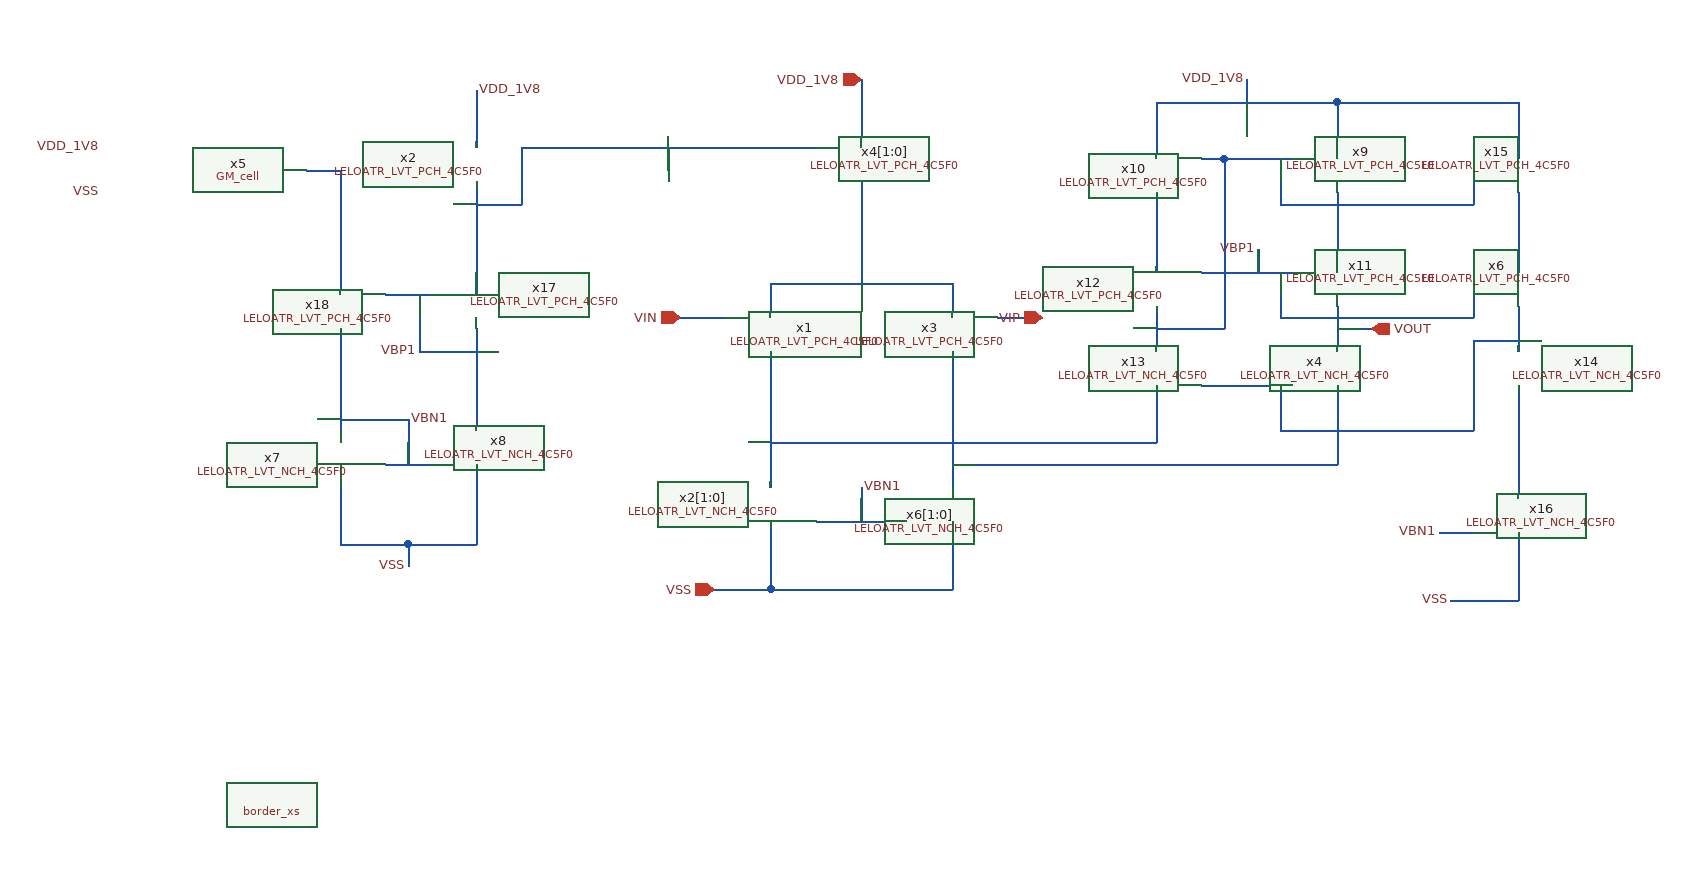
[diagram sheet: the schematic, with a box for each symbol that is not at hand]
v {xschem version=3.4.7 file_version=1.2}
G {}
K {}
V {}
S {}
E {}
P 4 1 20 30 {}
P 4 1 -120 -290 {}
N 440 -400 440 -380 {lab=#net1}
N 360 -430 400 -430 {lab=VIN}
N 640 -430 680 -430 {lab=VIP}
N 600 -400 600 -380 {lab=#net2}
N 440 -460 510 -460 {lab=#net3}
N 510 -460 600 -460 {lab=#net3}
N 520 -550 520 -460 {lab=#net3}
N 520 -640 520 -610 {lab=VDD_1V8}
N 100 -300 140 -300 {lab=VBN1}
N 120 -340 120 -300 {lab=VBN1}
N 60 -340 120 -340 {lab=VBN1}
N 120 -230 120 -210 {lab=VSS}
N 180 -340 180 -330 {lab=VBP1}
N 220 -580 220 -530 {lab=#net4}
N 180 -630 180 -610 {lab=VDD_1V8}
N 520 -610 520 -580 {lab=VDD_1V8}
N 180 -610 180 -580 {lab=VDD_1V8}
N 180 -300 180 -270 {lab=VSS}
N 60 -300 60 -270 {lab=VSS}
N 440 -250 440 -220 {lab=VSS}
N 600 -250 600 -220 {lab=VSS}
N 440 -380 440 -280 {lab=#net1}
N 600 -380 600 -280 {lab=#net2}
N 480 -250 560 -250 {lab=VBN1}
N 520 -280 520 -250 {lab=VBN1}
N 180 -530 220 -530 {lab=#net4}
N 220 -580 480 -580 {lab=#net4}
N 350 -580 350 -560 {lab=#net4}
N 780 -600 780 -570 {lab=VDD_1V8}
N 940 -600 940 -570 {lab=VDD_1V8}
N 780 -620 780 -600 {lab=VDD_1V8}
N 940 -620 940 -600 {lab=VDD_1V8}
N 780 -620 940 -620 {lab=VDD_1V8}
N 860 -640 860 -620 {lab=VDD_1V8}
N 820 -470 900 -470 {lab=VBP1}
N 780 -500 780 -470 {lab=#net5}
N 940 -500 940 -470 {lab=#net6}
N 780 -440 780 -400 {lab=#net7}
N 940 -440 940 -400 {lab=VOUT}
N 780 -540 780 -500 {lab=#net5}
N 940 -540 940 -500 {lab=#net6}
N 840 -570 840 -420 {lab=#net7}
N 780 -420 840 -420 {lab=#net7}
N 820 -370 900 -370 {lab=#net8}
N 940 -340 940 -300 {lab=#net2}
N 600 -300 940 -300 {lab=#net2}
N 780 -340 780 -320 {lab=#net1}
N 440 -320 780 -320 {lab=#net1}
N 440 -220 440 -190 {lab=VSS}
N 390 -190 440 -190 {lab=VSS}
N 600 -220 600 -190 {lab=VSS}
N 440 -190 600 -190 {lab=VSS}
N 780 -370 780 -340 {lab=#net1}
N 940 -370 940 -340 {lab=#net2}
N 940 -420 970 -420 {lab=VOUT}
N 870 -490 870 -470 {lab=VBP1}
N 60 -350 60 -330 {lab=VBN1}
N 60 -500 60 -490 {lab=#net9}
N 180 -360 180 -340 {lab=VBP1}
N 180 -270 180 -230 {lab=VSS}
N 120 -230 180 -230 {lab=VSS}
N 60 -230 120 -230 {lab=VSS}
N 60 -270 60 -230 {lab=VSS}
N 30 -560 60 -560 {lab=#net9}
N 440 -460 440 -430 {lab=#net3}
N 600 -460 600 -430 {lab=#net3}
N 180 -550 180 -500 {lab=#net4}
N 60 -560 60 -500 {lab=#net9}
N 1100 -210 1100 -180 {lab=VSS}
N 1040 -180 1100 -180 {lab=VSS}
N 1100 -240 1100 -210 {lab=VSS}
N 1100 -370 1100 -340 {lab=#net10}
N 1100 -340 1100 -270 {lab=#net10}
N 1030 -240 1060 -240 {lab=VBN1}
N 1100 -440 1100 -400 {lab=#net8}
N 1100 -540 1100 -500 {lab=#net11}
N 1100 -620 1100 -600 {lab=VDD_1V8}
N 940 -620 1100 -620 {lab=VDD_1V8}
N 1100 -600 1100 -570 {lab=VDD_1V8}
N 1100 -500 1100 -470 {lab=#net11}
N 820 -570 840 -570 {lab=#net7}
N 840 -570 900 -570 {lab=#net7}
N 890 -570 890 -530 {lab=#net7}
N 890 -530 1060 -530 {lab=#net7}
N 1060 -570 1060 -530 {lab=#net7}
N 890 -470 890 -430 {lab=VBP1}
N 890 -430 1060 -430 {lab=VBP1}
N 1060 -470 1060 -430 {lab=VBP1}
N 890 -370 890 -330 {lab=#net8}
N 890 -330 1060 -330 {lab=#net8}
N 1060 -370 1060 -330 {lab=#net8}
N 1060 -410 1060 -370 {lab=#net8}
N 1060 -410 1100 -410 {lab=#net8}
N 180 -500 180 -480 {lab=#net4}
N 100 -450 140 -450 {lab=VBP1}
N 60 -420 60 -350 {lab=VBN1}
N 180 -420 180 -360 {lab=VBP1}
N 60 -480 60 -450 {lab=#net9}
N 60 -490 60 -480 {lab=#net9}
N 180 -480 180 -450 {lab=#net4}
N 130 -450 130 -400 {lab=VBP1}
N 130 -400 180 -400 {lab=VBP1}
C {cborder/border_xs.sym} 0 0 0 0 {
user="nikolai"
company="wulff"}
C {devices/ipin.sym} 520 -640 0 0 {name=p1 lab=VDD_1V8}
C {devices/ipin.sym} 360 -430 0 0 {name=p4 lab=VIN}
C {devices/ipin.sym} 680 -430 2 0 {name=p5 lab=VIP}
C {devices/opin.sym} 970 -420 0 0 {name=p6 lab=VOUT}
C {LELO_ATR_SKY130A/LELOATR_LVT_PCH_4C5F0.sym} 400 -430 0 0 {name=x1 }
C {LELO_ATR_SKY130A/LELOATR_LVT_PCH_4C5F0.sym} 480 -580 0 0 {name=x4[1:0]}
C {LELO_ATR_SKY130A/LELOATR_LVT_PCH_4C5F0.sym} 640 -430 0 1 {name=x3 }
C {devices/ipin.sym} 390 -190 0 0 {name=p2 lab=VSS}
C {LELO_ATR_SKY130A/LELOATR_LVT_NCH_4C5F0.sym} 560 -250 0 0 {name=x6[1:0]}
C {LELO_ATR_SKY130A/LELOATR_LVT_NCH_4C5F0.sym} 480 -250 0 1 {name=x2[1:0]}
C {LELO_ATR_SKY130A/LELOATR_LVT_NCH_4C5F0.sym} 100 -300 0 1 {name=x7}
C {LELO_ATR_SKY130A/LELOATR_LVT_NCH_4C5F0.sym} 140 -300 0 0 {name=x8}
C {devices/lab_pin.sym} 120 -210 0 0 {name=p8 sig_type=std_logic lab=VSS}
C {LELO_ATR_SKY130A/LELOATR_LVT_PCH_4C5F0.sym} 220 -580 0 1 {name=x2}
C {devices/lab_pin.sym} 180 -630 0 1 {name=p9 sig_type=std_logic lab=VDD_1V8}
C {devices/lab_pin.sym} 120 -340 0 1 {name=p10 sig_type=std_logic lab=VBN1}
C {devices/lab_pin.sym} 520 -280 0 1 {name=p11 sig_type=std_logic lab=VBN1}
C {LELO_ATR_SKY130A/LELOATR_LVT_NCH_4C5F0.sym} 900 -370 0 0 {name=x4 }
C {LELO_ATR_SKY130A/LELOATR_LVT_PCH_4C5F0.sym} 900 -570 0 0 {name=x9}
C {LELO_ATR_SKY130A/LELOATR_LVT_PCH_4C5F0.sym} 820 -570 0 1 {name=x10}
C {devices/lab_pin.sym} 130 -400 0 0 {name=p12 sig_type=std_logic lab=VBP1}
C {devices/lab_pin.sym} 860 -640 0 0 {name=p13 sig_type=std_logic lab=VDD_1V8}
C {LELO_ATR_SKY130A/LELOATR_LVT_PCH_4C5F0.sym} 900 -470 0 0 {name=x11}
C {LELO_ATR_SKY130A/LELOATR_LVT_PCH_4C5F0.sym} 820 -470 0 1 {name=x12}
C {LELO_ATR_SKY130A/LELOATR_LVT_NCH_4C5F0.sym} 820 -370 0 1 {name=x13 }
C {devices/lab_pin.sym} 870 -490 0 0 {name=p14 sig_type=std_logic lab=VBP1}
C {LELO_ATR_SKY130A/LELOATR_LVT_PCH_4C5F0.sym} 1060 -570 0 0 {name=x15}
C {LELO_ATR_SKY130A/LELOATR_LVT_PCH_4C5F0.sym} 1060 -470 0 0 {name=x6}
C {LELO_ATR_SKY130A/LELOATR_LVT_NCH_4C5F0.sym} 1060 -370 0 0 {name=x14 }
C {LELO_ATR_SKY130A/LELOATR_LVT_NCH_4C5F0.sym} 1060 -240 0 0 {name=x16}
C {devices/lab_pin.sym} 1040 -180 0 0 {name=p16 sig_type=std_logic lab=VSS}
C {devices/lab_pin.sym} 1030 -240 0 0 {name=p17 sig_type=std_logic lab=VBN1}
C {LELO_GR01_SKY130A/GM_cell.sym} 0 -570 0 0 {name=x5}
C {devices/lab_pin.sym} -150 -580 0 0 {name=p3 sig_type=std_logic lab=VDD_1V8}
C {devices/lab_pin.sym} -150 -540 0 0 {name=p7 sig_type=std_logic lab=VSS}
C {LELO_ATR_SKY130A/LELOATR_LVT_PCH_4C5F0.sym} 140 -450 0 0 {name=x17 }
C {LELO_ATR_SKY130A/LELOATR_LVT_PCH_4C5F0.sym} 100 -450 0 1 {name=x18 }
